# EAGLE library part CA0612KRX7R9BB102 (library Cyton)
Capacitor,ceramic,multilayer,SMT,50V,1pF Source: Datasheet

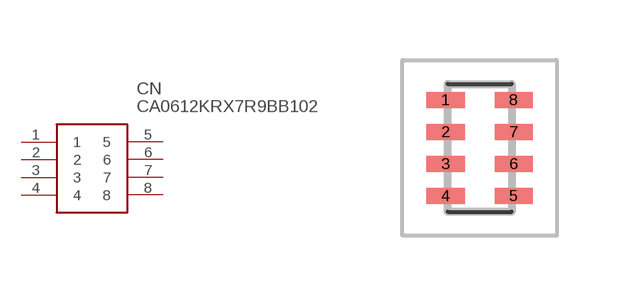
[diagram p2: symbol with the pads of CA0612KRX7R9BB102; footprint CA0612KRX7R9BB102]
Designator prefix CN

## CA0612KRX7R9BB102 (DESCRIPTION: Capacitor,ceramic,multilayer,SMT,50V,1pF; HEIGHT: mm; MANUFACTURER_NAME: YAGEO (PHYCOMP); MANUFACTURER_PART_NUMBER: CA0612KRX7R9BB102; RS_PART_NUMBER: 6169789; RS_PRICE-STOCK: http://uk.rs-online.com/web/p/products/6169789)  [CA0612KRX7R9BB102]
1  1
2  2
3  3
4  4
5  5
6  6
7  7
8  8

## Footprint CA0612KRX7R9BB102 (pad centres in mm)
CA0612KRX7R9BB102
smd 0.95 x 0.4: 1 -0.85,1.2; 2 -0.85,0.4; 3 -0.85,-0.4; 4 -0.85,-1.2; 5 0.85,-1.2; 6 0.85,-0.4; 7 0.85,0.4; 8 0.85,1.2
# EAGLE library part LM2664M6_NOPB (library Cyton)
1.8V to 5.5Vin Switched Capacitor Voltage Converter Source: Datasheet

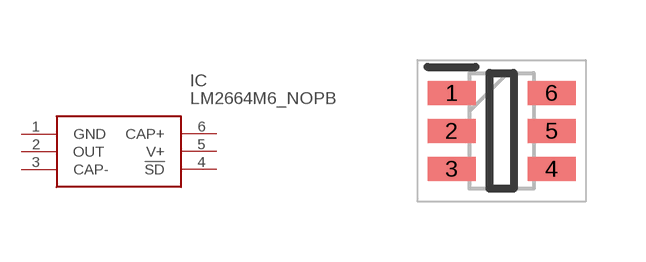
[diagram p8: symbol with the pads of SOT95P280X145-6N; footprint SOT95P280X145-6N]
Designator prefix IC

## LM2664M6_NOPB (DESCRIPTION: 1.8V to 5.5Vin Switched Capacitor Voltage Converter; HEIGHT: 1.45mm; MANUFACTURER_NAME: Texas Instruments; MANUFACTURER_PART_NUMBER: LM2664M6/NOPB; RS_PART_NUMBER: 5358792P; RS_PRICE-STOCK: http://uk.rs-online.com/web/p/products/5358792P)  [SOT95P280X145-6N]
1  GND  pwr
2  OUT  out
3  CAP-  pwr
4  !SD  in
5  V+  pwr
6  CAP+  pwr

## Footprint SOT95P280X145-6N (pad centres in mm)
DBV (R-PDSO-G6)
smd 1.2 x 0.6: 1 -1.25,0.95; 2 -1.25,0; 3 -1.25,-0.95; 4 1.25,-0.95; 5 1.25,0; 6 1.25,0.95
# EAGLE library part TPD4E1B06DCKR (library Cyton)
Texas Instruments TPD4E1B06DCKR Quad Bi-Directional ESD Protection Array, 45W peak, 6-Pin SC-70 Source: Datasheet

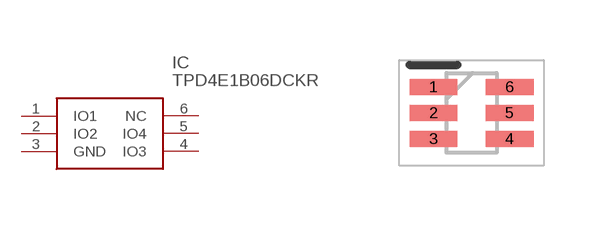
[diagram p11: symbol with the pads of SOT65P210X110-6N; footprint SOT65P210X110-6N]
Designator prefix IC

## TPD4E1B06DCKR (DESCRIPTION: Texas Instruments TPD4E1B06DCKR Quad Bi-Directional ESD Protection Array, 45W peak, 6-Pin SC-70; HEIGHT: 1.1mm; MANUFACTURER_NAME: Texas Instruments; MANUFACTURER_PART_NUMBER: TPD4E1B06DCKR; RS_PART_NUMBER: 8255330P; RS_PRICE-STOCK: http://uk.rs-online.com/web/p/products/8255330P)  [SOT65P210X110-6N]
1  IO1
2  IO2
3  GND  pwr
4  IO3
5  IO4
6  NC  nc

## Footprint SOT65P210X110-6N (pad centres in mm)
DCK (R-PDSO-G6)
smd 1.2 x 0.4: 1 -0.95,0.65; 2 -0.95,0; 3 -0.95,-0.65; 4 0.95,-0.65; 5 0.95,0; 6 0.95,0.65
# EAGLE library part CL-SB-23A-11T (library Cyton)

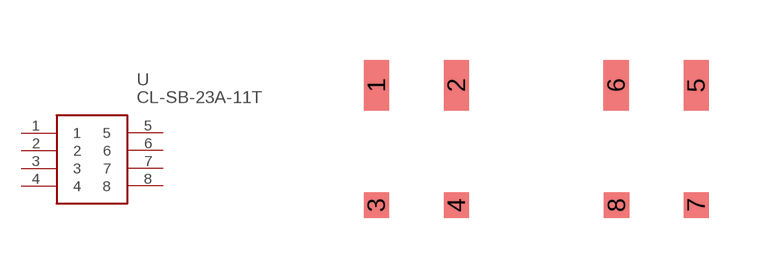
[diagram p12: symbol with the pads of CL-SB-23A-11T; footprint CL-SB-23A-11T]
Designator prefix -

## CL-SB-23A-11T  [CL-SB-23A-11T]
1  1
2  2
3  3
4  4
5  5
6  6
7  7
8  8

## Footprint CL-SB-23A-11T (pad centres in mm)
smd 0.635 x 1.27: 1 2.5,3.4; 2 4.5,3.4; 5 10.5,3.4; 6 8.5,3.4
smd 0.635 x 0.635: 3 2.5,0.4; 4 4.5,0.4; 7 10.5,0.4; 8 8.51,0.4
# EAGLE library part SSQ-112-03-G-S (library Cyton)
CONN SOCKET, 2.54MM, THT VERT, 12POS

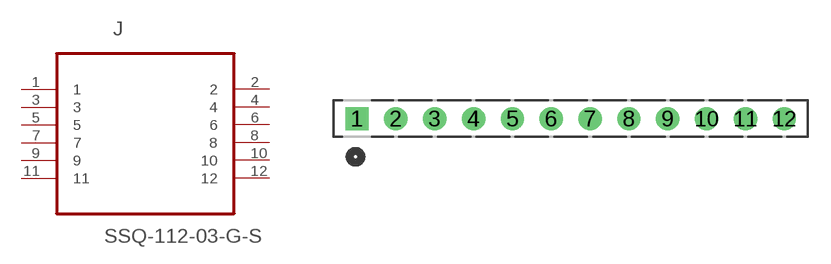
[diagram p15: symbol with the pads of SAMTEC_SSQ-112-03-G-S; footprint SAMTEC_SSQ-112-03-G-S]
Designator prefix J

## SSQ-112-03-G-S (AVAILABILITY: Unavailable; DESCRIPTION: SSQ Series .100 Tiger Buy™ Socket Strip, Square Tail; MF: Samtec Inc.; MP: SSQ-112-03-G-S; PACKAGE: None; PRICE: None)  [SAMTEC_SSQ-112-03-G-S]
1  1  pas
2  2  pas
3  3  pas
4  4  pas
5  5  pas
6  6  pas
7  7  pas
8  8  pas
9  9  pas
10  10  pas
11  11  pas
12  12  pas

## Footprint SAMTEC_SSQ-112-03-G-S (pad centres in mm)
drill 1.016 square: 1 -27.94,0
drill 1.016: 2 -25.4,0; 3 -22.86,0; 4 -20.32,0; 5 -17.78,0; 6 -15.24,0; 7 -12.7,0; 8 -10.16,0; 9 -7.62,0; 10 -5.08,0; 11 -2.54,0; 12 0,0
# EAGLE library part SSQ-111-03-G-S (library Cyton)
CONN SOCKET, 2.54MM, THT VERT, 11POS

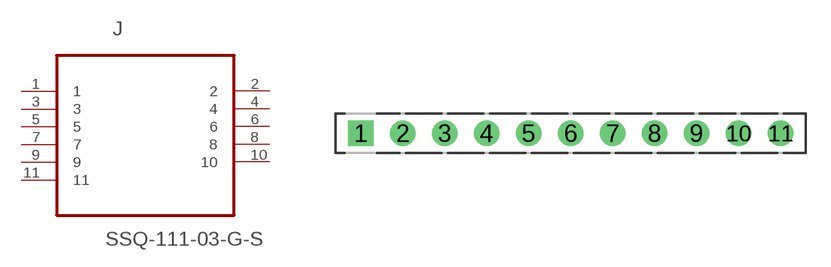
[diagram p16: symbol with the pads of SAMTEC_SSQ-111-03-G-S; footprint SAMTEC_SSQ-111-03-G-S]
Designator prefix J

## SSQ-111-03-G-S (AVAILABILITY: Unavailable; DESCRIPTION: SSQ Series .100 Tiger Buy™ Socket Strip, Square Tail; MF: Samtec; MP: SSQ-111-03-G-S; PACKAGE: None; PRICE: None)  [SAMTEC_SSQ-111-03-G-S]
1  1  pas
2  2  pas
3  3  pas
4  4  pas
5  5  pas
6  6  pas
7  7  pas
8  8  pas
9  9  pas
10  10  pas
11  11  pas

## Footprint SAMTEC_SSQ-111-03-G-S (pad centres in mm)
drill 1.016 square: 1 -25.4,0
drill 1.016: 2 -22.86,0; 3 -20.32,0; 4 -17.78,0; 5 -15.24,0; 6 -12.7,0; 7 -10.16,0; 8 -7.62,0; 9 -5.08,0; 10 -2.54,0; 11 0,0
